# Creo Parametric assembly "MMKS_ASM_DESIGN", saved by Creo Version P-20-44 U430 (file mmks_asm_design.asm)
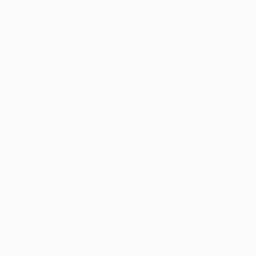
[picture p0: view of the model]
Units: millimeter Kilogram Sec (mmKs); MM, KILOGRAM, SECS

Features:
  1. datum plane "ASM_RIGHT"
  2. datum plane "ASM_TOP"
  3. datum plane "ASM_FRONT"
  4. coordinate system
